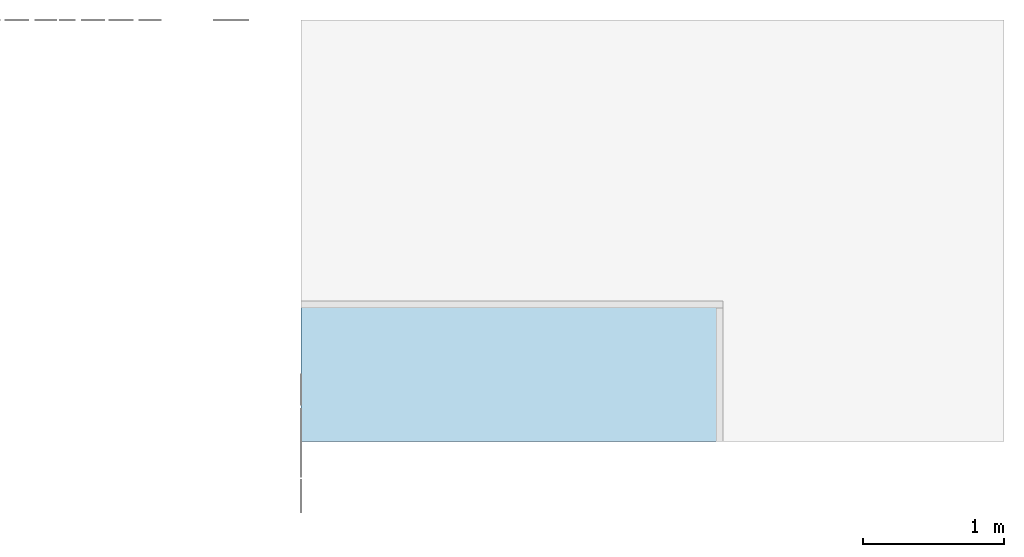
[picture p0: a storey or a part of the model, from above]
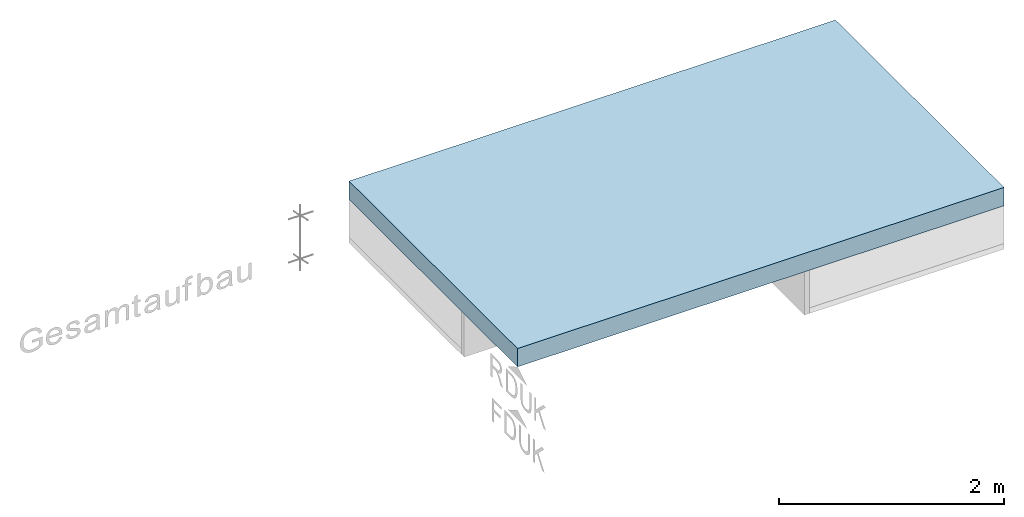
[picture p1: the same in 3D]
Properties of the parts of a building model (IFC4)

# File
Description: no view
File name: ÖBV_OEBV_Richtlinie_Abgehängtedecke.ifc
Time: 2024-03-13T09:53:49
Author: Oesterreichische Bautechnik Vereinigung
Organization: OEBV
Written by: ODA SDAI 24.5
Authorization: OEBV

# IfcSite, Liegenschaft
RefLatitude: 48, 8, 10, 320000; RefLongitude: 11, 41, 19, 320000

# IfcBuildingStorey, Geschoss 01
In: Gebäude
Elevation: 0 m

# IfcBuildingElementProxy (4)
In: Geschoss 01
Name | Allright_Bauteil_ID
RDUK | 0026Mak0000000200
FDUK | 0026Mak0000000211
macro | 0026Mak0000000222
macro | 0026Mak0000000241

# IfcCovering (4)
In: Geschoss 01
Name | Allright_Bauteil_ID
 | 0026ErE0000000190
 | 0026ErE0000001858
 | 0026ErE0000003552
 | 0026ErE0000003553

# IfcElementAssembly (5)
In: Geschoss 01
Name | Allright_Bauteil_ID
SpatialDim_Group | 0026Elg0000000201
SpatialDim_Group | 0026Elg0000000212
SpatialDim_Group | 0026Elg0000000223
SpatialDim_Group | 0026Elg0000000242
Abhangdecke | 0026Elg0000003554

# IfcSlab
In: Geschoss 01
AllplanAttributes - Allright_Bauteil_ID: 0026ErE0000000188
